VERSION 5.7 ;
BUSBITCHARS "[]" ;
DIVIDERCHAR "/" ;

PROPERTYDEFINITIONS
  MACRO CatenaDesignType STRING ;
END PROPERTYDEFINITIONS

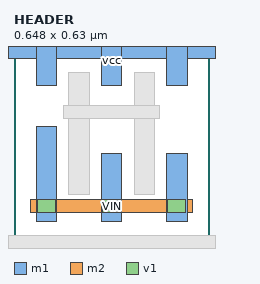
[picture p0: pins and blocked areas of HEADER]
MACRO HEADER
  CLASS CORE ;
  ORIGIN 0 0 ;
  FOREIGN HEADER 0 0 ;
  SIZE 0.648 BY 0.63 ;
  SYMMETRY X Y ;
  SITE CoreSite ;
  PIN vcc
    DIRECTION INOUT ;
    USE POWER ;
    SHAPE ABUTMENT ;
    PORT
      LAYER m1 ;
        RECT -0.034 0.608 0.682 0.652 ;
        RECT 0.506 0.518 0.574 0.652 ;
        RECT 0.29 0.518 0.358 0.652 ;
        RECT 0.074 0.518 0.142 0.652 ;
    END
  END vcc
  PIN VIN
    DIRECTION OUTPUT ;
    USE SIGNAL ;
    PORT
      LAYER m2 ;
        RECT 0.056 0.097 0.592 0.141 ;
      LAYER m1 ;
        RECT 0.506 0.068 0.574 0.292 ;
        RECT 0.29 0.068 0.358 0.292 ;
        RECT 0.074 0.068 0.142 0.382 ;
      LAYER v1 ;
        RECT 0.078 0.097 0.138 0.141 ;
        RECT 0.294 0.097 0.354 0.141 ;
        RECT 0.51 0.097 0.57 0.141 ;
    END
  END VIN
  OBS
    LAYER m1 ;
      RECT -0.034 -0.022 0.682 0.022 ;
      RECT 0.398 0.158 0.466 0.562 ;
      RECT 0.182 0.158 0.25 0.562 ;
    LAYER v1 ;
      RECT 0.402 0.408 0.462 0.452 ;
      RECT 0.186 0.408 0.246 0.452 ;
    LAYER m2 ;
      RECT 0.164 0.408 0.484 0.452 ;
  END
  PROPERTY CatenaDesignType "deviceLevel" ;
END HEADER

END LIBRARY
